VERSION 5.7 ;
  NOWIREEXTENSIONATPIN ON ;
  DIVIDERCHAR "/" ;
  BUSBITCHARS "[]" ;
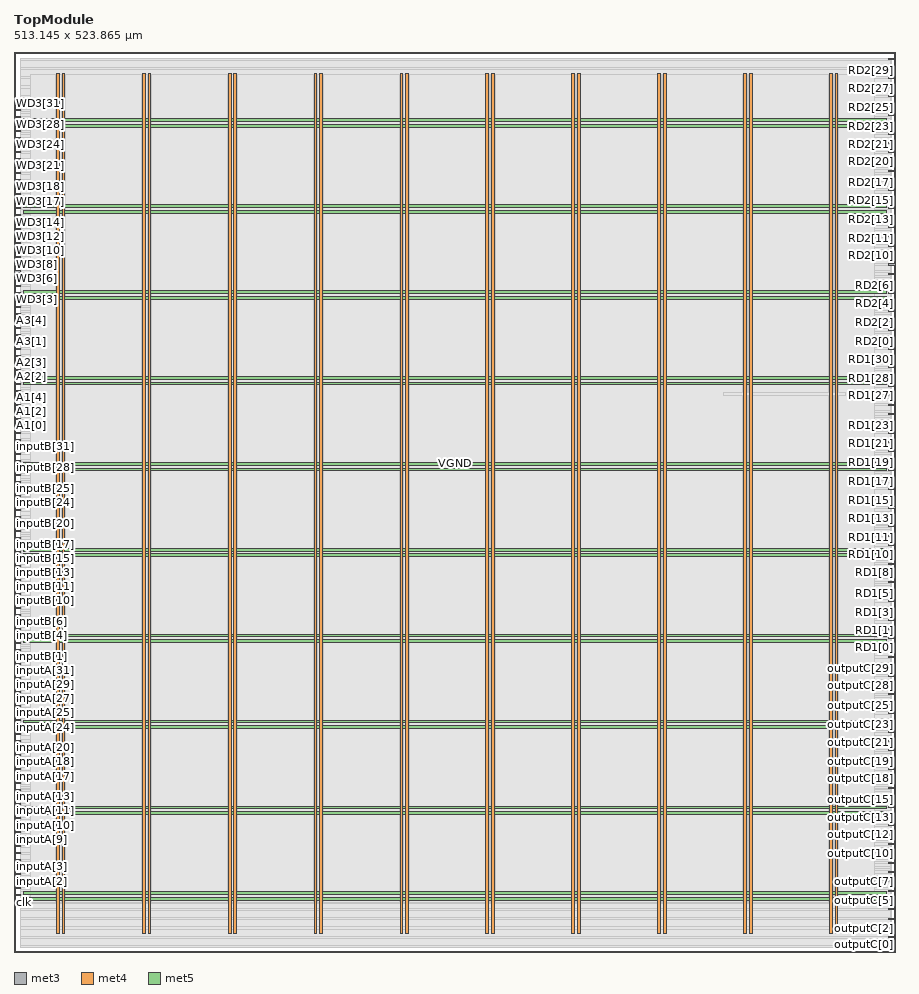
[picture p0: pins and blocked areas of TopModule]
MACRO TopModule
  CLASS BLOCK ;
  FOREIGN TopModule ;
  ORIGIN 0.000 0.000 ;
  SIZE 513.145 BY 523.865 ;
  PIN A1[0]
    DIRECTION INPUT ;
    USE SIGNAL ;
    ANTENNAGATEAREA 2.020500 ;
    ANTENNADIFFAREA 1.738800 ;
    PORT
      LAYER met3 ;
        RECT 0.000 306.040 4.000 306.640 ;
    END
  END A1[0]
  PIN A1[1]
    DIRECTION INPUT ;
    USE SIGNAL ;
    ANTENNAGATEAREA 1.203000 ;
    ANTENNADIFFAREA 1.738800 ;
    PORT
      LAYER met3 ;
        RECT 0.000 310.120 4.000 310.720 ;
    END
  END A1[1]
  PIN A1[2]
    DIRECTION INPUT ;
    USE SIGNAL ;
    ANTENNAGATEAREA 0.426000 ;
    ANTENNADIFFAREA 0.434700 ;
    PORT
      LAYER met3 ;
        RECT 0.000 314.200 4.000 314.800 ;
    END
  END A1[2]
  PIN A1[3]
    DIRECTION INPUT ;
    USE SIGNAL ;
    ANTENNAGATEAREA 1.540500 ;
    ANTENNADIFFAREA 2.608200 ;
    PORT
      LAYER met3 ;
        RECT 0.000 318.280 4.000 318.880 ;
    END
  END A1[3]
  PIN A1[4]
    DIRECTION INPUT ;
    USE SIGNAL ;
    ANTENNAGATEAREA 0.247500 ;
    ANTENNADIFFAREA 0.434700 ;
    PORT
      LAYER met3 ;
        RECT 0.000 322.360 4.000 322.960 ;
    END
  END A1[4]
  PIN A2[0]
    DIRECTION INPUT ;
    USE SIGNAL ;
    ANTENNAGATEAREA 1.629000 ;
    ANTENNADIFFAREA 1.738800 ;
    PORT
      LAYER met3 ;
        RECT 0.000 326.440 4.000 327.040 ;
    END
  END A2[0]
  PIN A2[1]
    DIRECTION INPUT ;
    USE SIGNAL ;
    ANTENNAGATEAREA 1.347000 ;
    ANTENNADIFFAREA 1.738800 ;
    PORT
      LAYER met3 ;
        RECT 0.000 330.520 4.000 331.120 ;
    END
  END A2[1]
  PIN A2[2]
    DIRECTION INPUT ;
    USE SIGNAL ;
    ANTENNAGATEAREA 0.247500 ;
    ANTENNADIFFAREA 0.434700 ;
    PORT
      LAYER met3 ;
        RECT 0.000 334.600 4.000 335.200 ;
    END
  END A2[2]
  PIN A2[3]
    DIRECTION INPUT ;
    USE SIGNAL ;
    ANTENNAGATEAREA 1.327500 ;
    ANTENNADIFFAREA 2.608200 ;
    PORT
      LAYER met3 ;
        RECT 0.000 338.680 4.000 339.280 ;
    END
  END A2[3]
  PIN A2[4]
    DIRECTION INPUT ;
    USE SIGNAL ;
    ANTENNAGATEAREA 0.247500 ;
    ANTENNADIFFAREA 0.434700 ;
    PORT
      LAYER met3 ;
        RECT 0.000 342.760 4.000 343.360 ;
    END
  END A2[4]
  PIN A3[0]
    DIRECTION INPUT ;
    USE SIGNAL ;
    ANTENNAGATEAREA 0.213000 ;
    ANTENNADIFFAREA 0.434700 ;
    PORT
      LAYER met3 ;
        RECT 0.000 346.840 4.000 347.440 ;
    END
  END A3[0]
  PIN A3[1]
    DIRECTION INPUT ;
    USE SIGNAL ;
    ANTENNAGATEAREA 0.247500 ;
    ANTENNADIFFAREA 0.434700 ;
    PORT
      LAYER met3 ;
        RECT 0.000 350.920 4.000 351.520 ;
    END
  END A3[1]
  PIN A3[2]
    DIRECTION INPUT ;
    USE SIGNAL ;
    ANTENNAGATEAREA 0.213000 ;
    ANTENNADIFFAREA 0.434700 ;
    PORT
      LAYER met3 ;
        RECT 0.000 355.000 4.000 355.600 ;
    END
  END A3[2]
  PIN A3[3]
    DIRECTION INPUT ;
    USE SIGNAL ;
    ANTENNAGATEAREA 0.213000 ;
    ANTENNADIFFAREA 0.434700 ;
    PORT
      LAYER met3 ;
        RECT 0.000 359.080 4.000 359.680 ;
    END
  END A3[3]
  PIN A3[4]
    DIRECTION INPUT ;
    USE SIGNAL ;
    ANTENNAGATEAREA 0.213000 ;
    ANTENNADIFFAREA 0.434700 ;
    PORT
      LAYER met3 ;
        RECT 0.000 363.160 4.000 363.760 ;
    END
  END A3[4]
  PIN RD1[0]
    DIRECTION OUTPUT ;
    USE SIGNAL ;
    ANTENNADIFFAREA 0.445500 ;
    PORT
      LAYER met3 ;
        RECT 509.145 176.840 513.145 177.440 ;
    END
  END RD1[0]
  PIN RD1[10]
    DIRECTION OUTPUT ;
    USE SIGNAL ;
    ANTENNADIFFAREA 0.445500 ;
    PORT
      LAYER met3 ;
        RECT 509.145 231.240 513.145 231.840 ;
    END
  END RD1[10]
  PIN RD1[11]
    DIRECTION OUTPUT ;
    USE SIGNAL ;
    ANTENNADIFFAREA 0.445500 ;
    PORT
      LAYER met3 ;
        RECT 509.145 236.680 513.145 237.280 ;
    END
  END RD1[11]
  PIN RD1[12]
    DIRECTION OUTPUT ;
    USE SIGNAL ;
    ANTENNADIFFAREA 0.445500 ;
    PORT
      LAYER met3 ;
        RECT 509.145 242.120 513.145 242.720 ;
    END
  END RD1[12]
  PIN RD1[13]
    DIRECTION OUTPUT ;
    USE SIGNAL ;
    ANTENNADIFFAREA 0.445500 ;
    PORT
      LAYER met3 ;
        RECT 509.145 247.560 513.145 248.160 ;
    END
  END RD1[13]
  PIN RD1[14]
    DIRECTION OUTPUT ;
    USE SIGNAL ;
    ANTENNADIFFAREA 0.445500 ;
    PORT
      LAYER met3 ;
        RECT 509.145 253.000 513.145 253.600 ;
    END
  END RD1[14]
  PIN RD1[15]
    DIRECTION OUTPUT ;
    USE SIGNAL ;
    ANTENNADIFFAREA 0.445500 ;
    PORT
      LAYER met3 ;
        RECT 509.145 258.440 513.145 259.040 ;
    END
  END RD1[15]
  PIN RD1[16]
    DIRECTION OUTPUT ;
    USE SIGNAL ;
    ANTENNADIFFAREA 0.445500 ;
    PORT
      LAYER met3 ;
        RECT 509.145 263.880 513.145 264.480 ;
    END
  END RD1[16]
  PIN RD1[17]
    DIRECTION OUTPUT ;
    USE SIGNAL ;
    ANTENNADIFFAREA 0.445500 ;
    PORT
      LAYER met3 ;
        RECT 509.145 269.320 513.145 269.920 ;
    END
  END RD1[17]
  PIN RD1[18]
    DIRECTION OUTPUT ;
    USE SIGNAL ;
    ANTENNADIFFAREA 0.445500 ;
    PORT
      LAYER met3 ;
        RECT 509.145 274.760 513.145 275.360 ;
    END
  END RD1[18]
  PIN RD1[19]
    DIRECTION OUTPUT ;
    USE SIGNAL ;
    ANTENNADIFFAREA 0.445500 ;
    PORT
      LAYER met3 ;
        RECT 509.145 280.200 513.145 280.800 ;
    END
  END RD1[19]
  PIN RD1[1]
    DIRECTION OUTPUT ;
    USE SIGNAL ;
    ANTENNADIFFAREA 0.445500 ;
    PORT
      LAYER met3 ;
        RECT 509.145 182.280 513.145 182.880 ;
    END
  END RD1[1]
  PIN RD1[20]
    DIRECTION OUTPUT ;
    USE SIGNAL ;
    ANTENNADIFFAREA 0.445500 ;
    PORT
      LAYER met3 ;
        RECT 509.145 285.640 513.145 286.240 ;
    END
  END RD1[20]
  PIN RD1[21]
    DIRECTION OUTPUT ;
    USE SIGNAL ;
    ANTENNADIFFAREA 0.445500 ;
    PORT
      LAYER met3 ;
        RECT 509.145 291.080 513.145 291.680 ;
    END
  END RD1[21]
  PIN RD1[22]
    DIRECTION OUTPUT ;
    USE SIGNAL ;
    ANTENNADIFFAREA 0.445500 ;
    PORT
      LAYER met3 ;
        RECT 509.145 296.520 513.145 297.120 ;
    END
  END RD1[22]
  PIN RD1[23]
    DIRECTION OUTPUT ;
    USE SIGNAL ;
    ANTENNADIFFAREA 0.445500 ;
    PORT
      LAYER met3 ;
        RECT 509.145 301.960 513.145 302.560 ;
    END
  END RD1[23]
  PIN RD1[24]
    DIRECTION OUTPUT ;
    USE SIGNAL ;
    ANTENNADIFFAREA 0.445500 ;
    PORT
      LAYER met3 ;
        RECT 509.145 307.400 513.145 308.000 ;
    END
  END RD1[24]
  PIN RD1[25]
    DIRECTION OUTPUT ;
    USE SIGNAL ;
    ANTENNADIFFAREA 0.445500 ;
    PORT
      LAYER met3 ;
        RECT 509.145 312.840 513.145 313.440 ;
    END
  END RD1[25]
  PIN RD1[26]
    DIRECTION OUTPUT ;
    USE SIGNAL ;
    ANTENNADIFFAREA 0.445500 ;
    PORT
      LAYER met3 ;
        RECT 509.145 318.280 513.145 318.880 ;
    END
  END RD1[26]
  PIN RD1[27]
    DIRECTION OUTPUT ;
    USE SIGNAL ;
    ANTENNADIFFAREA 0.445500 ;
    PORT
      LAYER met3 ;
        RECT 509.145 323.720 513.145 324.320 ;
    END
  END RD1[27]
  PIN RD1[28]
    DIRECTION OUTPUT ;
    USE SIGNAL ;
    ANTENNADIFFAREA 0.445500 ;
    PORT
      LAYER met3 ;
        RECT 509.145 329.160 513.145 329.760 ;
    END
  END RD1[28]
  PIN RD1[29]
    DIRECTION OUTPUT ;
    USE SIGNAL ;
    ANTENNADIFFAREA 0.445500 ;
    PORT
      LAYER met3 ;
        RECT 509.145 334.600 513.145 335.200 ;
    END
  END RD1[29]
  PIN RD1[2]
    DIRECTION OUTPUT ;
    USE SIGNAL ;
    ANTENNADIFFAREA 0.445500 ;
    PORT
      LAYER met3 ;
        RECT 509.145 187.720 513.145 188.320 ;
    END
  END RD1[2]
  PIN RD1[30]
    DIRECTION OUTPUT ;
    USE SIGNAL ;
    ANTENNADIFFAREA 0.445500 ;
    PORT
      LAYER met3 ;
        RECT 509.145 340.040 513.145 340.640 ;
    END
  END RD1[30]
  PIN RD1[31]
    DIRECTION OUTPUT ;
    USE SIGNAL ;
    ANTENNADIFFAREA 0.445500 ;
    PORT
      LAYER met3 ;
        RECT 509.145 345.480 513.145 346.080 ;
    END
  END RD1[31]
  PIN RD1[3]
    DIRECTION OUTPUT ;
    USE SIGNAL ;
    ANTENNADIFFAREA 0.445500 ;
    PORT
      LAYER met3 ;
        RECT 509.145 193.160 513.145 193.760 ;
    END
  END RD1[3]
  PIN RD1[4]
    DIRECTION OUTPUT ;
    USE SIGNAL ;
    ANTENNADIFFAREA 0.445500 ;
    PORT
      LAYER met3 ;
        RECT 509.145 198.600 513.145 199.200 ;
    END
  END RD1[4]
  PIN RD1[5]
    DIRECTION OUTPUT ;
    USE SIGNAL ;
    ANTENNADIFFAREA 0.445500 ;
    PORT
      LAYER met3 ;
        RECT 509.145 204.040 513.145 204.640 ;
    END
  END RD1[5]
  PIN RD1[6]
    DIRECTION OUTPUT ;
    USE SIGNAL ;
    ANTENNADIFFAREA 0.445500 ;
    PORT
      LAYER met3 ;
        RECT 509.145 209.480 513.145 210.080 ;
    END
  END RD1[6]
  PIN RD1[7]
    DIRECTION OUTPUT ;
    USE SIGNAL ;
    ANTENNADIFFAREA 0.445500 ;
    PORT
      LAYER met3 ;
        RECT 509.145 214.920 513.145 215.520 ;
    END
  END RD1[7]
  PIN RD1[8]
    DIRECTION OUTPUT ;
    USE SIGNAL ;
    ANTENNADIFFAREA 0.445500 ;
    PORT
      LAYER met3 ;
        RECT 509.145 220.360 513.145 220.960 ;
    END
  END RD1[8]
  PIN RD1[9]
    DIRECTION OUTPUT ;
    USE SIGNAL ;
    ANTENNADIFFAREA 0.445500 ;
    PORT
      LAYER met3 ;
        RECT 509.145 225.800 513.145 226.400 ;
    END
  END RD1[9]
  PIN RD2[0]
    DIRECTION OUTPUT ;
    USE SIGNAL ;
    ANTENNADIFFAREA 0.445500 ;
    PORT
      LAYER met3 ;
        RECT 509.145 350.920 513.145 351.520 ;
    END
  END RD2[0]
  PIN RD2[10]
    DIRECTION OUTPUT ;
    USE SIGNAL ;
    ANTENNADIFFAREA 0.445500 ;
    PORT
      LAYER met3 ;
        RECT 509.145 405.320 513.145 405.920 ;
    END
  END RD2[10]
  PIN RD2[11]
    DIRECTION OUTPUT ;
    USE SIGNAL ;
    ANTENNADIFFAREA 0.445500 ;
    PORT
      LAYER met3 ;
        RECT 509.145 410.760 513.145 411.360 ;
    END
  END RD2[11]
  PIN RD2[12]
    DIRECTION OUTPUT ;
    USE SIGNAL ;
    ANTENNADIFFAREA 0.445500 ;
    PORT
      LAYER met3 ;
        RECT 509.145 416.200 513.145 416.800 ;
    END
  END RD2[12]
  PIN RD2[13]
    DIRECTION OUTPUT ;
    USE SIGNAL ;
    ANTENNADIFFAREA 0.445500 ;
    PORT
      LAYER met3 ;
        RECT 509.145 421.640 513.145 422.240 ;
    END
  END RD2[13]
  PIN RD2[14]
    DIRECTION OUTPUT ;
    USE SIGNAL ;
    ANTENNADIFFAREA 0.445500 ;
    PORT
      LAYER met3 ;
        RECT 509.145 427.080 513.145 427.680 ;
    END
  END RD2[14]
  PIN RD2[15]
    DIRECTION OUTPUT ;
    USE SIGNAL ;
    ANTENNADIFFAREA 0.445500 ;
    PORT
      LAYER met3 ;
        RECT 509.145 432.520 513.145 433.120 ;
    END
  END RD2[15]
  PIN RD2[16]
    DIRECTION OUTPUT ;
    USE SIGNAL ;
    ANTENNADIFFAREA 0.445500 ;
    PORT
      LAYER met3 ;
        RECT 509.145 437.960 513.145 438.560 ;
    END
  END RD2[16]
  PIN RD2[17]
    DIRECTION OUTPUT ;
    USE SIGNAL ;
    ANTENNADIFFAREA 0.445500 ;
    PORT
      LAYER met3 ;
        RECT 509.145 443.400 513.145 444.000 ;
    END
  END RD2[17]
  PIN RD2[18]
    DIRECTION OUTPUT ;
    USE SIGNAL ;
    ANTENNADIFFAREA 0.445500 ;
    PORT
      LAYER met3 ;
        RECT 509.145 448.840 513.145 449.440 ;
    END
  END RD2[18]
  PIN RD2[19]
    DIRECTION OUTPUT ;
    USE SIGNAL ;
    ANTENNADIFFAREA 0.445500 ;
    PORT
      LAYER met3 ;
        RECT 509.145 454.280 513.145 454.880 ;
    END
  END RD2[19]
  PIN RD2[1]
    DIRECTION OUTPUT ;
    USE SIGNAL ;
    ANTENNADIFFAREA 0.445500 ;
    PORT
      LAYER met3 ;
        RECT 509.145 356.360 513.145 356.960 ;
    END
  END RD2[1]
  PIN RD2[20]
    DIRECTION OUTPUT ;
    USE SIGNAL ;
    ANTENNADIFFAREA 0.445500 ;
    PORT
      LAYER met3 ;
        RECT 509.145 459.720 513.145 460.320 ;
    END
  END RD2[20]
  PIN RD2[21]
    DIRECTION OUTPUT ;
    USE SIGNAL ;
    ANTENNADIFFAREA 0.445500 ;
    PORT
      LAYER met3 ;
        RECT 509.145 465.160 513.145 465.760 ;
    END
  END RD2[21]
  PIN RD2[22]
    DIRECTION OUTPUT ;
    USE SIGNAL ;
    ANTENNADIFFAREA 0.445500 ;
    PORT
      LAYER met3 ;
        RECT 509.145 470.600 513.145 471.200 ;
    END
  END RD2[22]
  PIN RD2[23]
    DIRECTION OUTPUT ;
    USE SIGNAL ;
    ANTENNADIFFAREA 0.445500 ;
    PORT
      LAYER met3 ;
        RECT 509.145 476.040 513.145 476.640 ;
    END
  END RD2[23]
  PIN RD2[24]
    DIRECTION OUTPUT ;
    USE SIGNAL ;
    ANTENNADIFFAREA 0.445500 ;
    PORT
      LAYER met3 ;
        RECT 509.145 481.480 513.145 482.080 ;
    END
  END RD2[24]
  PIN RD2[25]
    DIRECTION OUTPUT ;
    USE SIGNAL ;
    ANTENNADIFFAREA 0.445500 ;
    PORT
      LAYER met3 ;
        RECT 509.145 486.920 513.145 487.520 ;
    END
  END RD2[25]
  PIN RD2[26]
    DIRECTION OUTPUT ;
    USE SIGNAL ;
    ANTENNADIFFAREA 0.445500 ;
    PORT
      LAYER met3 ;
        RECT 509.145 492.360 513.145 492.960 ;
    END
  END RD2[26]
  PIN RD2[27]
    DIRECTION OUTPUT ;
    USE SIGNAL ;
    ANTENNADIFFAREA 0.445500 ;
    PORT
      LAYER met3 ;
        RECT 509.145 497.800 513.145 498.400 ;
    END
  END RD2[27]
  PIN RD2[28]
    DIRECTION OUTPUT ;
    USE SIGNAL ;
    ANTENNADIFFAREA 0.445500 ;
    PORT
      LAYER met3 ;
        RECT 509.145 503.240 513.145 503.840 ;
    END
  END RD2[28]
  PIN RD2[29]
    DIRECTION OUTPUT ;
    USE SIGNAL ;
    ANTENNADIFFAREA 0.445500 ;
    PORT
      LAYER met3 ;
        RECT 509.145 508.680 513.145 509.280 ;
    END
  END RD2[29]
  PIN RD2[2]
    DIRECTION OUTPUT ;
    USE SIGNAL ;
    ANTENNADIFFAREA 0.445500 ;
    PORT
      LAYER met3 ;
        RECT 509.145 361.800 513.145 362.400 ;
    END
  END RD2[2]
  PIN RD2[30]
    DIRECTION OUTPUT ;
    USE SIGNAL ;
    ANTENNADIFFAREA 0.445500 ;
    PORT
      LAYER met3 ;
        RECT 509.145 514.120 513.145 514.720 ;
    END
  END RD2[30]
  PIN RD2[31]
    DIRECTION OUTPUT ;
    USE SIGNAL ;
    ANTENNADIFFAREA 0.795200 ;
    PORT
      LAYER met3 ;
        RECT 509.145 519.560 513.145 520.160 ;
    END
  END RD2[31]
  PIN RD2[3]
    DIRECTION OUTPUT ;
    USE SIGNAL ;
    ANTENNADIFFAREA 0.445500 ;
    PORT
      LAYER met3 ;
        RECT 509.145 367.240 513.145 367.840 ;
    END
  END RD2[3]
  PIN RD2[4]
    DIRECTION OUTPUT ;
    USE SIGNAL ;
    ANTENNADIFFAREA 0.445500 ;
    PORT
      LAYER met3 ;
        RECT 509.145 372.680 513.145 373.280 ;
    END
  END RD2[4]
  PIN RD2[5]
    DIRECTION OUTPUT ;
    USE SIGNAL ;
    ANTENNADIFFAREA 0.445500 ;
    PORT
      LAYER met3 ;
        RECT 509.145 378.120 513.145 378.720 ;
    END
  END RD2[5]
  PIN RD2[6]
    DIRECTION OUTPUT ;
    USE SIGNAL ;
    ANTENNADIFFAREA 0.445500 ;
    PORT
      LAYER met3 ;
        RECT 509.145 383.560 513.145 384.160 ;
    END
  END RD2[6]
  PIN RD2[7]
    DIRECTION OUTPUT ;
    USE SIGNAL ;
    ANTENNADIFFAREA 0.445500 ;
    PORT
      LAYER met3 ;
        RECT 509.145 389.000 513.145 389.600 ;
    END
  END RD2[7]
  PIN RD2[8]
    DIRECTION OUTPUT ;
    USE SIGNAL ;
    ANTENNADIFFAREA 0.445500 ;
    PORT
      LAYER met3 ;
        RECT 509.145 394.440 513.145 395.040 ;
    END
  END RD2[8]
  PIN RD2[9]
    DIRECTION OUTPUT ;
    USE SIGNAL ;
    ANTENNADIFFAREA 0.445500 ;
    PORT
      LAYER met3 ;
        RECT 509.145 399.880 513.145 400.480 ;
    END
  END RD2[9]
  PIN VGND
    DIRECTION INOUT ;
    USE GROUND ;
    PORT
      LAYER met4 ;
        RECT 28.020 10.640 29.620 511.600 ;
    END
    PORT
      LAYER met4 ;
        RECT 78.020 10.640 79.620 511.600 ;
    END
    PORT
      LAYER met4 ;
        RECT 128.020 10.640 129.620 511.600 ;
    END
    PORT
      LAYER met4 ;
        RECT 178.020 10.640 179.620 511.600 ;
    END
    PORT
      LAYER met4 ;
        RECT 228.020 10.640 229.620 511.600 ;
    END
    PORT
      LAYER met4 ;
        RECT 278.020 10.640 279.620 511.600 ;
    END
    PORT
      LAYER met4 ;
        RECT 328.020 10.640 329.620 511.600 ;
    END
    PORT
      LAYER met4 ;
        RECT 378.020 10.640 379.620 511.600 ;
    END
    PORT
      LAYER met4 ;
        RECT 428.020 10.640 429.620 511.600 ;
    END
    PORT
      LAYER met4 ;
        RECT 478.020 10.640 479.620 511.600 ;
    END
    PORT
      LAYER met5 ;
        RECT 5.280 33.380 507.620 34.980 ;
    END
    PORT
      LAYER met5 ;
        RECT 5.280 83.380 507.620 84.980 ;
    END
    PORT
      LAYER met5 ;
        RECT 5.280 133.380 507.620 134.980 ;
    END
    PORT
      LAYER met5 ;
        RECT 5.280 183.380 507.620 184.980 ;
    END
    PORT
      LAYER met5 ;
        RECT 5.280 233.380 507.620 234.980 ;
    END
    PORT
      LAYER met5 ;
        RECT 5.280 283.380 507.620 284.980 ;
    END
    PORT
      LAYER met5 ;
        RECT 5.280 333.380 507.620 334.980 ;
    END
    PORT
      LAYER met5 ;
        RECT 5.280 383.380 507.620 384.980 ;
    END
    PORT
      LAYER met5 ;
        RECT 5.280 433.380 507.620 434.980 ;
    END
    PORT
      LAYER met5 ;
        RECT 5.280 483.380 507.620 484.980 ;
    END
  END VGND
  PIN VPWR
    DIRECTION INOUT ;
    USE POWER ;
    PORT
      LAYER met4 ;
        RECT 24.720 10.640 26.320 511.600 ;
    END
    PORT
      LAYER met4 ;
        RECT 74.720 10.640 76.320 511.600 ;
    END
    PORT
      LAYER met4 ;
        RECT 124.720 10.640 126.320 511.600 ;
    END
    PORT
      LAYER met4 ;
        RECT 174.720 10.640 176.320 511.600 ;
    END
    PORT
      LAYER met4 ;
        RECT 224.720 10.640 226.320 511.600 ;
    END
    PORT
      LAYER met4 ;
        RECT 274.720 10.640 276.320 511.600 ;
    END
    PORT
      LAYER met4 ;
        RECT 324.720 10.640 326.320 511.600 ;
    END
    PORT
      LAYER met4 ;
        RECT 374.720 10.640 376.320 511.600 ;
    END
    PORT
      LAYER met4 ;
        RECT 424.720 10.640 426.320 511.600 ;
    END
    PORT
      LAYER met4 ;
        RECT 474.720 10.640 476.320 511.600 ;
    END
    PORT
      LAYER met5 ;
        RECT 5.280 30.080 507.620 31.680 ;
    END
    PORT
      LAYER met5 ;
        RECT 5.280 80.080 507.620 81.680 ;
    END
    PORT
      LAYER met5 ;
        RECT 5.280 130.080 507.620 131.680 ;
    END
    PORT
      LAYER met5 ;
        RECT 5.280 180.080 507.620 181.680 ;
    END
    PORT
      LAYER met5 ;
        RECT 5.280 230.080 507.620 231.680 ;
    END
    PORT
      LAYER met5 ;
        RECT 5.280 280.080 507.620 281.680 ;
    END
    PORT
      LAYER met5 ;
        RECT 5.280 330.080 507.620 331.680 ;
    END
    PORT
      LAYER met5 ;
        RECT 5.280 380.080 507.620 381.680 ;
    END
    PORT
      LAYER met5 ;
        RECT 5.280 430.080 507.620 431.680 ;
    END
    PORT
      LAYER met5 ;
        RECT 5.280 480.080 507.620 481.680 ;
    END
  END VPWR
  PIN WD3[0]
    DIRECTION INPUT ;
    USE SIGNAL ;
    ANTENNAGATEAREA 0.213000 ;
    ANTENNADIFFAREA 0.434700 ;
    PORT
      LAYER met3 ;
        RECT 0.000 367.240 4.000 367.840 ;
    END
  END WD3[0]
  PIN WD3[10]
    DIRECTION INPUT ;
    USE SIGNAL ;
    ANTENNAGATEAREA 0.213000 ;
    ANTENNADIFFAREA 0.434700 ;
    PORT
      LAYER met3 ;
        RECT 0.000 408.040 4.000 408.640 ;
    END
  END WD3[10]
  PIN WD3[11]
    DIRECTION INPUT ;
    USE SIGNAL ;
    ANTENNAGATEAREA 0.213000 ;
    ANTENNADIFFAREA 0.434700 ;
    PORT
      LAYER met3 ;
        RECT 0.000 412.120 4.000 412.720 ;
    END
  END WD3[11]
  PIN WD3[12]
    DIRECTION INPUT ;
    USE SIGNAL ;
    ANTENNAGATEAREA 0.213000 ;
    ANTENNADIFFAREA 0.434700 ;
    PORT
      LAYER met3 ;
        RECT 0.000 416.200 4.000 416.800 ;
    END
  END WD3[12]
  PIN WD3[13]
    DIRECTION INPUT ;
    USE SIGNAL ;
    ANTENNAGATEAREA 0.213000 ;
    ANTENNADIFFAREA 0.434700 ;
    PORT
      LAYER met3 ;
        RECT 0.000 420.280 4.000 420.880 ;
    END
  END WD3[13]
  PIN WD3[14]
    DIRECTION INPUT ;
    USE SIGNAL ;
    ANTENNAGATEAREA 0.213000 ;
    ANTENNADIFFAREA 0.434700 ;
    PORT
      LAYER met3 ;
        RECT 0.000 424.360 4.000 424.960 ;
    END
  END WD3[14]
  PIN WD3[15]
    DIRECTION INPUT ;
    USE SIGNAL ;
    ANTENNAGATEAREA 0.213000 ;
    ANTENNADIFFAREA 0.434700 ;
    PORT
      LAYER met3 ;
        RECT 0.000 428.440 4.000 429.040 ;
    END
  END WD3[15]
  PIN WD3[16]
    DIRECTION INPUT ;
    USE SIGNAL ;
    ANTENNAGATEAREA 0.213000 ;
    ANTENNADIFFAREA 0.434700 ;
    PORT
      LAYER met3 ;
        RECT 0.000 432.520 4.000 433.120 ;
    END
  END WD3[16]
  PIN WD3[17]
    DIRECTION INPUT ;
    USE SIGNAL ;
    ANTENNAGATEAREA 0.213000 ;
    ANTENNADIFFAREA 0.434700 ;
    PORT
      LAYER met3 ;
        RECT 0.000 436.600 4.000 437.200 ;
    END
  END WD3[17]
  PIN WD3[18]
    DIRECTION INPUT ;
    USE SIGNAL ;
    ANTENNAGATEAREA 0.213000 ;
    ANTENNADIFFAREA 0.434700 ;
    PORT
      LAYER met3 ;
        RECT 0.000 440.680 4.000 441.280 ;
    END
  END WD3[18]
  PIN WD3[19]
    DIRECTION INPUT ;
    USE SIGNAL ;
    ANTENNAGATEAREA 0.213000 ;
    ANTENNADIFFAREA 0.434700 ;
    PORT
      LAYER met3 ;
        RECT 0.000 444.760 4.000 445.360 ;
    END
  END WD3[19]
  PIN WD3[1]
    DIRECTION INPUT ;
    USE SIGNAL ;
    ANTENNAGATEAREA 0.213000 ;
    ANTENNADIFFAREA 0.434700 ;
    PORT
      LAYER met3 ;
        RECT 0.000 371.320 4.000 371.920 ;
    END
  END WD3[1]
  PIN WD3[20]
    DIRECTION INPUT ;
    USE SIGNAL ;
    ANTENNAGATEAREA 0.213000 ;
    ANTENNADIFFAREA 0.434700 ;
    PORT
      LAYER met3 ;
        RECT 0.000 448.840 4.000 449.440 ;
    END
  END WD3[20]
  PIN WD3[21]
    DIRECTION INPUT ;
    USE SIGNAL ;
    ANTENNAGATEAREA 0.213000 ;
    ANTENNADIFFAREA 0.434700 ;
    PORT
      LAYER met3 ;
        RECT 0.000 452.920 4.000 453.520 ;
    END
  END WD3[21]
  PIN WD3[22]
    DIRECTION INPUT ;
    USE SIGNAL ;
    ANTENNAGATEAREA 0.159000 ;
    ANTENNADIFFAREA 0.434700 ;
    PORT
      LAYER met3 ;
        RECT 0.000 457.000 4.000 457.600 ;
    END
  END WD3[22]
  PIN WD3[23]
    DIRECTION INPUT ;
    USE SIGNAL ;
    ANTENNAGATEAREA 0.213000 ;
    ANTENNADIFFAREA 0.434700 ;
    PORT
      LAYER met3 ;
        RECT 0.000 461.080 4.000 461.680 ;
    END
  END WD3[23]
  PIN WD3[24]
    DIRECTION INPUT ;
    USE SIGNAL ;
    ANTENNAGATEAREA 0.213000 ;
    ANTENNADIFFAREA 0.434700 ;
    PORT
      LAYER met3 ;
        RECT 0.000 465.160 4.000 465.760 ;
    END
  END WD3[24]
  PIN WD3[25]
    DIRECTION INPUT ;
    USE SIGNAL ;
    ANTENNAGATEAREA 0.213000 ;
    ANTENNADIFFAREA 0.434700 ;
    PORT
      LAYER met3 ;
        RECT 0.000 469.240 4.000 469.840 ;
    END
  END WD3[25]
  PIN WD3[26]
    DIRECTION INPUT ;
    USE SIGNAL ;
    ANTENNAGATEAREA 0.213000 ;
    ANTENNADIFFAREA 0.434700 ;
    PORT
      LAYER met3 ;
        RECT 0.000 473.320 4.000 473.920 ;
    END
  END WD3[26]
  PIN WD3[27]
    DIRECTION INPUT ;
    USE SIGNAL ;
    ANTENNAGATEAREA 0.213000 ;
    ANTENNADIFFAREA 0.434700 ;
    PORT
      LAYER met3 ;
        RECT 0.000 477.400 4.000 478.000 ;
    END
  END WD3[27]
  PIN WD3[28]
    DIRECTION INPUT ;
    USE SIGNAL ;
    ANTENNAGATEAREA 0.213000 ;
    ANTENNADIFFAREA 0.434700 ;
    PORT
      LAYER met3 ;
        RECT 0.000 481.480 4.000 482.080 ;
    END
  END WD3[28]
  PIN WD3[29]
    DIRECTION INPUT ;
    USE SIGNAL ;
    ANTENNAGATEAREA 0.213000 ;
    ANTENNADIFFAREA 0.434700 ;
    PORT
      LAYER met3 ;
        RECT 0.000 485.560 4.000 486.160 ;
    END
  END WD3[29]
  PIN WD3[2]
    DIRECTION INPUT ;
    USE SIGNAL ;
    ANTENNAGATEAREA 0.213000 ;
    ANTENNADIFFAREA 0.434700 ;
    PORT
      LAYER met3 ;
        RECT 0.000 375.400 4.000 376.000 ;
    END
  END WD3[2]
  PIN WD3[30]
    DIRECTION INPUT ;
    USE SIGNAL ;
    ANTENNAGATEAREA 0.247500 ;
    ANTENNADIFFAREA 0.434700 ;
    PORT
      LAYER met3 ;
        RECT 0.000 489.640 4.000 490.240 ;
    END
  END WD3[30]
  PIN WD3[31]
    DIRECTION INPUT ;
    USE SIGNAL ;
    ANTENNAGATEAREA 0.247500 ;
    ANTENNADIFFAREA 0.434700 ;
    PORT
      LAYER met3 ;
        RECT 0.000 493.720 4.000 494.320 ;
    END
  END WD3[31]
  PIN WD3[3]
    DIRECTION INPUT ;
    USE SIGNAL ;
    ANTENNAGATEAREA 0.247500 ;
    ANTENNADIFFAREA 0.434700 ;
    PORT
      LAYER met3 ;
        RECT 0.000 379.480 4.000 380.080 ;
    END
  END WD3[3]
  PIN WD3[4]
    DIRECTION INPUT ;
    USE SIGNAL ;
    ANTENNAGATEAREA 0.213000 ;
    ANTENNADIFFAREA 0.434700 ;
    PORT
      LAYER met3 ;
        RECT 0.000 383.560 4.000 384.160 ;
    END
  END WD3[4]
  PIN WD3[5]
    DIRECTION INPUT ;
    USE SIGNAL ;
    ANTENNAGATEAREA 0.213000 ;
    ANTENNADIFFAREA 0.434700 ;
    PORT
      LAYER met3 ;
        RECT 0.000 387.640 4.000 388.240 ;
    END
  END WD3[5]
  PIN WD3[6]
    DIRECTION INPUT ;
    USE SIGNAL ;
    ANTENNAGATEAREA 0.247500 ;
    ANTENNADIFFAREA 0.434700 ;
    PORT
      LAYER met3 ;
        RECT 0.000 391.720 4.000 392.320 ;
    END
  END WD3[6]
  PIN WD3[7]
    DIRECTION INPUT ;
    USE SIGNAL ;
    ANTENNAGATEAREA 0.247500 ;
    ANTENNADIFFAREA 0.434700 ;
    PORT
      LAYER met3 ;
        RECT 0.000 395.800 4.000 396.400 ;
    END
  END WD3[7]
  PIN WD3[8]
    DIRECTION INPUT ;
    USE SIGNAL ;
    ANTENNAGATEAREA 0.213000 ;
    ANTENNADIFFAREA 0.434700 ;
    PORT
      LAYER met3 ;
        RECT 0.000 399.880 4.000 400.480 ;
    END
  END WD3[8]
  PIN WD3[9]
    DIRECTION INPUT ;
    USE SIGNAL ;
    ANTENNAGATEAREA 0.247500 ;
    ANTENNADIFFAREA 0.434700 ;
    PORT
      LAYER met3 ;
        RECT 0.000 403.960 4.000 404.560 ;
    END
  END WD3[9]
  PIN WE3
    DIRECTION INPUT ;
    USE SIGNAL ;
    ANTENNAGATEAREA 0.247500 ;
    ANTENNADIFFAREA 0.434700 ;
    PORT
      LAYER met3 ;
        RECT 0.000 301.960 4.000 302.560 ;
    END
  END WE3
  PIN clk
    DIRECTION INPUT ;
    USE SIGNAL ;
    ANTENNAGATEAREA 0.852000 ;
    ANTENNADIFFAREA 0.434700 ;
    PORT
      LAYER met3 ;
        RECT 0.000 28.600 4.000 29.200 ;
    END
  END clk
  PIN inputA[0]
    DIRECTION INPUT ;
    USE SIGNAL ;
    ANTENNAGATEAREA 0.196500 ;
    ANTENNADIFFAREA 0.434700 ;
    PORT
      LAYER met3 ;
        RECT 0.000 32.680 4.000 33.280 ;
    END
  END inputA[0]
  PIN inputA[10]
    DIRECTION INPUT ;
    USE SIGNAL ;
    ANTENNAGATEAREA 0.196500 ;
    ANTENNADIFFAREA 0.434700 ;
    PORT
      LAYER met3 ;
        RECT 0.000 73.480 4.000 74.080 ;
    END
  END inputA[10]
  PIN inputA[11]
    DIRECTION INPUT ;
    USE SIGNAL ;
    ANTENNAGATEAREA 0.196500 ;
    ANTENNADIFFAREA 0.434700 ;
    PORT
      LAYER met3 ;
        RECT 0.000 77.560 4.000 78.160 ;
    END
  END inputA[11]
  PIN inputA[12]
    DIRECTION INPUT ;
    USE SIGNAL ;
    ANTENNAGATEAREA 0.126000 ;
    ANTENNADIFFAREA 0.434700 ;
    PORT
      LAYER met3 ;
        RECT 0.000 81.640 4.000 82.240 ;
    END
  END inputA[12]
  PIN inputA[13]
    DIRECTION INPUT ;
    USE SIGNAL ;
    ANTENNAGATEAREA 0.126000 ;
    ANTENNADIFFAREA 0.434700 ;
    PORT
      LAYER met3 ;
        RECT 0.000 85.720 4.000 86.320 ;
    END
  END inputA[13]
  PIN inputA[14]
    DIRECTION INPUT ;
    USE SIGNAL ;
    ANTENNAGATEAREA 0.196500 ;
    ANTENNADIFFAREA 0.434700 ;
    PORT
      LAYER met3 ;
        RECT 0.000 89.800 4.000 90.400 ;
    END
  END inputA[14]
  PIN inputA[15]
    DIRECTION INPUT ;
    USE SIGNAL ;
    ANTENNAGATEAREA 0.196500 ;
    ANTENNADIFFAREA 0.434700 ;
    PORT
      LAYER met3 ;
        RECT 0.000 93.880 4.000 94.480 ;
    END
  END inputA[15]
  PIN inputA[16]
    DIRECTION INPUT ;
    USE SIGNAL ;
    ANTENNAGATEAREA 0.196500 ;
    ANTENNADIFFAREA 0.434700 ;
    PORT
      LAYER met3 ;
        RECT 0.000 97.960 4.000 98.560 ;
    END
  END inputA[16]
  PIN inputA[17]
    DIRECTION INPUT ;
    USE SIGNAL ;
    ANTENNAGATEAREA 0.196500 ;
    ANTENNADIFFAREA 0.434700 ;
    PORT
      LAYER met3 ;
        RECT 0.000 102.040 4.000 102.640 ;
    END
  END inputA[17]
  PIN inputA[18]
    DIRECTION INPUT ;
    USE SIGNAL ;
    ANTENNAGATEAREA 0.196500 ;
    ANTENNADIFFAREA 0.434700 ;
    PORT
      LAYER met3 ;
        RECT 0.000 106.120 4.000 106.720 ;
    END
  END inputA[18]
  PIN inputA[19]
    DIRECTION INPUT ;
    USE SIGNAL ;
    ANTENNAGATEAREA 0.213000 ;
    ANTENNADIFFAREA 0.434700 ;
    PORT
      LAYER met3 ;
        RECT 0.000 110.200 4.000 110.800 ;
    END
  END inputA[19]
  PIN inputA[1]
    DIRECTION INPUT ;
    USE SIGNAL ;
    ANTENNAGATEAREA 0.196500 ;
    ANTENNADIFFAREA 0.434700 ;
    PORT
      LAYER met3 ;
        RECT 0.000 36.760 4.000 37.360 ;
    END
  END inputA[1]
  PIN inputA[20]
    DIRECTION INPUT ;
    USE SIGNAL ;
    ANTENNAGATEAREA 0.126000 ;
    ANTENNADIFFAREA 0.434700 ;
    PORT
      LAYER met3 ;
        RECT 0.000 114.280 4.000 114.880 ;
    END
  END inputA[20]
  PIN inputA[21]
    DIRECTION INPUT ;
    USE SIGNAL ;
    ANTENNAGATEAREA 0.213000 ;
    ANTENNADIFFAREA 0.434700 ;
    PORT
      LAYER met3 ;
        RECT 0.000 118.360 4.000 118.960 ;
    END
  END inputA[21]
  PIN inputA[22]
    DIRECTION INPUT ;
    USE SIGNAL ;
    ANTENNAGATEAREA 0.196500 ;
    ANTENNADIFFAREA 0.434700 ;
    PORT
      LAYER met3 ;
        RECT 0.000 122.440 4.000 123.040 ;
    END
  END inputA[22]
  PIN inputA[23]
    DIRECTION INPUT ;
    USE SIGNAL ;
    ANTENNAGATEAREA 0.196500 ;
    ANTENNADIFFAREA 0.434700 ;
    PORT
      LAYER met3 ;
        RECT 0.000 126.520 4.000 127.120 ;
    END
  END inputA[23]
  PIN inputA[24]
    DIRECTION INPUT ;
    USE SIGNAL ;
    ANTENNAGATEAREA 0.196500 ;
    ANTENNADIFFAREA 0.434700 ;
    PORT
      LAYER met3 ;
        RECT 0.000 130.600 4.000 131.200 ;
    END
  END inputA[24]
  PIN inputA[25]
    DIRECTION INPUT ;
    USE SIGNAL ;
    ANTENNAGATEAREA 0.196500 ;
    ANTENNADIFFAREA 0.434700 ;
    PORT
      LAYER met3 ;
        RECT 0.000 134.680 4.000 135.280 ;
    END
  END inputA[25]
  PIN inputA[26]
    DIRECTION INPUT ;
    USE SIGNAL ;
    ANTENNAGATEAREA 0.213000 ;
    ANTENNADIFFAREA 0.434700 ;
    PORT
      LAYER met3 ;
        RECT 0.000 138.760 4.000 139.360 ;
    END
  END inputA[26]
  PIN inputA[27]
    DIRECTION INPUT ;
    USE SIGNAL ;
    ANTENNAGATEAREA 0.213000 ;
    ANTENNADIFFAREA 0.434700 ;
    PORT
      LAYER met3 ;
        RECT 0.000 142.840 4.000 143.440 ;
    END
  END inputA[27]
  PIN inputA[28]
    DIRECTION INPUT ;
    USE SIGNAL ;
    ANTENNAGATEAREA 0.196500 ;
    ANTENNADIFFAREA 0.434700 ;
    PORT
      LAYER met3 ;
        RECT 0.000 146.920 4.000 147.520 ;
    END
  END inputA[28]
  PIN inputA[29]
    DIRECTION INPUT ;
    USE SIGNAL ;
    ANTENNAGATEAREA 0.126000 ;
    ANTENNADIFFAREA 0.434700 ;
    PORT
      LAYER met3 ;
        RECT 0.000 151.000 4.000 151.600 ;
    END
  END inputA[29]
  PIN inputA[2]
    DIRECTION INPUT ;
    USE SIGNAL ;
    ANTENNAGATEAREA 0.196500 ;
    ANTENNADIFFAREA 0.434700 ;
    PORT
      LAYER met3 ;
        RECT 0.000 40.840 4.000 41.440 ;
    END
  END inputA[2]
  PIN inputA[30]
    DIRECTION INPUT ;
    USE SIGNAL ;
    ANTENNAGATEAREA 0.213000 ;
    ANTENNADIFFAREA 0.434700 ;
    PORT
      LAYER met3 ;
        RECT 0.000 155.080 4.000 155.680 ;
    END
  END inputA[30]
  PIN inputA[31]
    DIRECTION INPUT ;
    USE SIGNAL ;
    ANTENNAGATEAREA 0.196500 ;
    ANTENNADIFFAREA 0.434700 ;
    PORT
      LAYER met3 ;
        RECT 0.000 159.160 4.000 159.760 ;
    END
  END inputA[31]
  PIN inputA[3]
    DIRECTION INPUT ;
    USE SIGNAL ;
    ANTENNAGATEAREA 0.196500 ;
    ANTENNADIFFAREA 0.434700 ;
    PORT
      LAYER met3 ;
        RECT 0.000 44.920 4.000 45.520 ;
    END
  END inputA[3]
  PIN inputA[4]
    DIRECTION INPUT ;
    USE SIGNAL ;
    ANTENNAGATEAREA 0.126000 ;
    ANTENNADIFFAREA 0.434700 ;
    PORT
      LAYER met3 ;
        RECT 0.000 49.000 4.000 49.600 ;
    END
  END inputA[4]
  PIN inputA[5]
    DIRECTION INPUT ;
    USE SIGNAL ;
    ANTENNAGATEAREA 0.126000 ;
    ANTENNADIFFAREA 0.434700 ;
    PORT
      LAYER met3 ;
        RECT 0.000 53.080 4.000 53.680 ;
    END
  END inputA[5]
  PIN inputA[6]
    DIRECTION INPUT ;
    USE SIGNAL ;
    ANTENNAGATEAREA 0.196500 ;
    ANTENNADIFFAREA 0.434700 ;
    PORT
      LAYER met3 ;
        RECT 0.000 57.160 4.000 57.760 ;
    END
  END inputA[6]
  PIN inputA[7]
    DIRECTION INPUT ;
    USE SIGNAL ;
    ANTENNAGATEAREA 0.196500 ;
    ANTENNADIFFAREA 0.434700 ;
    PORT
      LAYER met3 ;
        RECT 0.000 61.240 4.000 61.840 ;
    END
  END inputA[7]
  PIN inputA[8]
    DIRECTION INPUT ;
    USE SIGNAL ;
    ANTENNAGATEAREA 0.196500 ;
    ANTENNADIFFAREA 0.434700 ;
    PORT
      LAYER met3 ;
        RECT 0.000 65.320 4.000 65.920 ;
    END
  END inputA[8]
  PIN inputA[9]
    DIRECTION INPUT ;
    USE SIGNAL ;
    ANTENNAGATEAREA 0.196500 ;
    ANTENNADIFFAREA 0.434700 ;
    PORT
      LAYER met3 ;
        RECT 0.000 69.400 4.000 70.000 ;
    END
  END inputA[9]
  PIN inputB[0]
    DIRECTION INPUT ;
    USE SIGNAL ;
    ANTENNAGATEAREA 0.196500 ;
    ANTENNADIFFAREA 0.434700 ;
    PORT
      LAYER met3 ;
        RECT 0.000 163.240 4.000 163.840 ;
    END
  END inputB[0]
  PIN inputB[10]
    DIRECTION INPUT ;
    USE SIGNAL ;
    ANTENNAGATEAREA 0.196500 ;
    ANTENNADIFFAREA 0.434700 ;
    PORT
      LAYER met3 ;
        RECT 0.000 204.040 4.000 204.640 ;
    END
  END inputB[10]
  PIN inputB[11]
    DIRECTION INPUT ;
    USE SIGNAL ;
    ANTENNAGATEAREA 0.196500 ;
    ANTENNADIFFAREA 0.434700 ;
    PORT
      LAYER met3 ;
        RECT 0.000 208.120 4.000 208.720 ;
    END
  END inputB[11]
  PIN inputB[12]
    DIRECTION INPUT ;
    USE SIGNAL ;
    ANTENNAGATEAREA 0.213000 ;
    ANTENNADIFFAREA 0.434700 ;
    PORT
      LAYER met3 ;
        RECT 0.000 212.200 4.000 212.800 ;
    END
  END inputB[12]
  PIN inputB[13]
    DIRECTION INPUT ;
    USE SIGNAL ;
    ANTENNAGATEAREA 0.126000 ;
    ANTENNADIFFAREA 0.434700 ;
    PORT
      LAYER met3 ;
        RECT 0.000 216.280 4.000 216.880 ;
    END
  END inputB[13]
  PIN inputB[14]
    DIRECTION INPUT ;
    USE SIGNAL ;
    ANTENNAGATEAREA 0.196500 ;
    ANTENNADIFFAREA 0.434700 ;
    PORT
      LAYER met3 ;
        RECT 0.000 220.360 4.000 220.960 ;
    END
  END inputB[14]
  PIN inputB[15]
    DIRECTION INPUT ;
    USE SIGNAL ;
    ANTENNAGATEAREA 0.196500 ;
    ANTENNADIFFAREA 0.434700 ;
    PORT
      LAYER met3 ;
        RECT 0.000 224.440 4.000 225.040 ;
    END
  END inputB[15]
  PIN inputB[16]
    DIRECTION INPUT ;
    USE SIGNAL ;
    ANTENNAGATEAREA 0.196500 ;
    ANTENNADIFFAREA 0.434700 ;
    PORT
      LAYER met3 ;
        RECT 0.000 228.520 4.000 229.120 ;
    END
  END inputB[16]
  PIN inputB[17]
    DIRECTION INPUT ;
    USE SIGNAL ;
    ANTENNAGATEAREA 0.196500 ;
    ANTENNADIFFAREA 0.434700 ;
    PORT
      LAYER met3 ;
        RECT 0.000 232.600 4.000 233.200 ;
    END
  END inputB[17]
  PIN inputB[18]
    DIRECTION INPUT ;
    USE SIGNAL ;
    ANTENNAGATEAREA 0.196500 ;
    ANTENNADIFFAREA 0.434700 ;
    PORT
      LAYER met3 ;
        RECT 0.000 236.680 4.000 237.280 ;
    END
  END inputB[18]
  PIN inputB[19]
    DIRECTION INPUT ;
    USE SIGNAL ;
    ANTENNAGATEAREA 0.196500 ;
    ANTENNADIFFAREA 0.434700 ;
    PORT
      LAYER met3 ;
        RECT 0.000 240.760 4.000 241.360 ;
    END
  END inputB[19]
  PIN inputB[1]
    DIRECTION INPUT ;
    USE SIGNAL ;
    ANTENNAGATEAREA 0.495000 ;
    ANTENNADIFFAREA 0.434700 ;
    PORT
      LAYER met3 ;
        RECT 0.000 167.320 4.000 167.920 ;
    END
  END inputB[1]
  PIN inputB[20]
    DIRECTION INPUT ;
    USE SIGNAL ;
    ANTENNAGATEAREA 0.196500 ;
    ANTENNADIFFAREA 0.434700 ;
    PORT
      LAYER met3 ;
        RECT 0.000 244.840 4.000 245.440 ;
    END
  END inputB[20]
  PIN inputB[21]
    DIRECTION INPUT ;
    USE SIGNAL ;
    ANTENNAGATEAREA 0.126000 ;
    ANTENNADIFFAREA 0.434700 ;
    PORT
      LAYER met3 ;
        RECT 0.000 248.920 4.000 249.520 ;
    END
  END inputB[21]
  PIN inputB[22]
    DIRECTION INPUT ;
    USE SIGNAL ;
    ANTENNAGATEAREA 0.196500 ;
    ANTENNADIFFAREA 0.434700 ;
    PORT
      LAYER met3 ;
        RECT 0.000 253.000 4.000 253.600 ;
    END
  END inputB[22]
  PIN inputB[23]
    DIRECTION INPUT ;
    USE SIGNAL ;
    ANTENNAGATEAREA 0.196500 ;
    ANTENNADIFFAREA 0.434700 ;
    PORT
      LAYER met3 ;
        RECT 0.000 257.080 4.000 257.680 ;
    END
  END inputB[23]
  PIN inputB[24]
    DIRECTION INPUT ;
    USE SIGNAL ;
    ANTENNAGATEAREA 0.213000 ;
    ANTENNADIFFAREA 0.434700 ;
    PORT
      LAYER met3 ;
        RECT 0.000 261.160 4.000 261.760 ;
    END
  END inputB[24]
  PIN inputB[25]
    DIRECTION INPUT ;
    USE SIGNAL ;
    ANTENNAGATEAREA 0.126000 ;
    ANTENNADIFFAREA 0.434700 ;
    PORT
      LAYER met3 ;
        RECT 0.000 265.240 4.000 265.840 ;
    END
  END inputB[25]
  PIN inputB[26]
    DIRECTION INPUT ;
    USE SIGNAL ;
    ANTENNAGATEAREA 0.213000 ;
    ANTENNADIFFAREA 0.434700 ;
    PORT
      LAYER met3 ;
        RECT 0.000 269.320 4.000 269.920 ;
    END
  END inputB[26]
  PIN inputB[27]
    DIRECTION INPUT ;
    USE SIGNAL ;
    ANTENNAGATEAREA 0.213000 ;
    ANTENNADIFFAREA 0.434700 ;
    PORT
      LAYER met3 ;
        RECT 0.000 273.400 4.000 274.000 ;
    END
  END inputB[27]
  PIN inputB[28]
    DIRECTION INPUT ;
    USE SIGNAL ;
    ANTENNAGATEAREA 0.213000 ;
    ANTENNADIFFAREA 0.434700 ;
    PORT
      LAYER met3 ;
        RECT 0.000 277.480 4.000 278.080 ;
    END
  END inputB[28]
  PIN inputB[29]
    DIRECTION INPUT ;
    USE SIGNAL ;
    ANTENNAGATEAREA 0.213000 ;
    ANTENNADIFFAREA 0.434700 ;
    PORT
      LAYER met3 ;
        RECT 0.000 281.560 4.000 282.160 ;
    END
  END inputB[29]
  PIN inputB[2]
    DIRECTION INPUT ;
    USE SIGNAL ;
    ANTENNAGATEAREA 0.247500 ;
    ANTENNADIFFAREA 0.434700 ;
    PORT
      LAYER met3 ;
        RECT 0.000 171.400 4.000 172.000 ;
    END
  END inputB[2]
  PIN inputB[30]
    DIRECTION INPUT ;
    USE SIGNAL ;
    ANTENNAGATEAREA 0.213000 ;
    ANTENNADIFFAREA 0.434700 ;
    PORT
      LAYER met3 ;
        RECT 0.000 285.640 4.000 286.240 ;
    END
  END inputB[30]
  PIN inputB[31]
    DIRECTION INPUT ;
    USE SIGNAL ;
    ANTENNAGATEAREA 0.126000 ;
    ANTENNADIFFAREA 0.434700 ;
    PORT
      LAYER met3 ;
        RECT 0.000 289.720 4.000 290.320 ;
    END
  END inputB[31]
  PIN inputB[3]
    DIRECTION INPUT ;
    USE SIGNAL ;
    ANTENNAGATEAREA 0.126000 ;
    ANTENNADIFFAREA 0.434700 ;
    PORT
      LAYER met3 ;
        RECT 0.000 175.480 4.000 176.080 ;
    END
  END inputB[3]
  PIN inputB[4]
    DIRECTION INPUT ;
    USE SIGNAL ;
    ANTENNAGATEAREA 0.196500 ;
    ANTENNADIFFAREA 0.434700 ;
    PORT
      LAYER met3 ;
        RECT 0.000 179.560 4.000 180.160 ;
    END
  END inputB[4]
  PIN inputB[5]
    DIRECTION INPUT ;
    USE SIGNAL ;
    ANTENNAGATEAREA 0.196500 ;
    ANTENNADIFFAREA 0.434700 ;
    PORT
      LAYER met3 ;
        RECT 0.000 183.640 4.000 184.240 ;
    END
  END inputB[5]
  PIN inputB[6]
    DIRECTION INPUT ;
    USE SIGNAL ;
    ANTENNAGATEAREA 0.126000 ;
    ANTENNADIFFAREA 0.434700 ;
    PORT
      LAYER met3 ;
        RECT 0.000 187.720 4.000 188.320 ;
    END
  END inputB[6]
  PIN inputB[7]
    DIRECTION INPUT ;
    USE SIGNAL ;
    ANTENNAGATEAREA 0.196500 ;
    ANTENNADIFFAREA 0.434700 ;
    PORT
      LAYER met3 ;
        RECT 0.000 191.800 4.000 192.400 ;
    END
  END inputB[7]
  PIN inputB[8]
    DIRECTION INPUT ;
    USE SIGNAL ;
    ANTENNAGATEAREA 0.196500 ;
    ANTENNADIFFAREA 0.434700 ;
    PORT
      LAYER met3 ;
        RECT 0.000 195.880 4.000 196.480 ;
    END
  END inputB[8]
  PIN inputB[9]
    DIRECTION INPUT ;
    USE SIGNAL ;
    ANTENNAGATEAREA 0.196500 ;
    ANTENNADIFFAREA 0.434700 ;
    PORT
      LAYER met3 ;
        RECT 0.000 199.960 4.000 200.560 ;
    END
  END inputB[9]
  PIN opcode[0]
    DIRECTION INPUT ;
    USE SIGNAL ;
    ANTENNAGATEAREA 0.213000 ;
    ANTENNADIFFAREA 0.434700 ;
    PORT
      LAYER met3 ;
        RECT 0.000 293.800 4.000 294.400 ;
    END
  END opcode[0]
  PIN opcode[1]
    DIRECTION INPUT ;
    USE SIGNAL ;
    ANTENNAGATEAREA 0.213000 ;
    ANTENNADIFFAREA 0.434700 ;
    PORT
      LAYER met3 ;
        RECT 0.000 297.880 4.000 298.480 ;
    END
  END opcode[1]
  PIN outputC[0]
    DIRECTION OUTPUT ;
    USE SIGNAL ;
    ANTENNADIFFAREA 0.795200 ;
    PORT
      LAYER met3 ;
        RECT 509.145 2.760 513.145 3.360 ;
    END
  END outputC[0]
  PIN outputC[10]
    DIRECTION OUTPUT ;
    USE SIGNAL ;
    ANTENNADIFFAREA 0.445500 ;
    PORT
      LAYER met3 ;
        RECT 509.145 57.160 513.145 57.760 ;
    END
  END outputC[10]
  PIN outputC[11]
    DIRECTION OUTPUT ;
    USE SIGNAL ;
    ANTENNADIFFAREA 0.445500 ;
    PORT
      LAYER met3 ;
        RECT 509.145 62.600 513.145 63.200 ;
    END
  END outputC[11]
  PIN outputC[12]
    DIRECTION OUTPUT ;
    USE SIGNAL ;
    ANTENNADIFFAREA 0.445500 ;
    PORT
      LAYER met3 ;
        RECT 509.145 68.040 513.145 68.640 ;
    END
  END outputC[12]
  PIN outputC[13]
    DIRECTION OUTPUT ;
    USE SIGNAL ;
    ANTENNADIFFAREA 0.445500 ;
    PORT
      LAYER met3 ;
        RECT 509.145 73.480 513.145 74.080 ;
    END
  END outputC[13]
  PIN outputC[14]
    DIRECTION OUTPUT ;
    USE SIGNAL ;
    ANTENNADIFFAREA 0.445500 ;
    PORT
      LAYER met3 ;
        RECT 509.145 78.920 513.145 79.520 ;
    END
  END outputC[14]
  PIN outputC[15]
    DIRECTION OUTPUT ;
    USE SIGNAL ;
    ANTENNADIFFAREA 0.445500 ;
    PORT
      LAYER met3 ;
        RECT 509.145 84.360 513.145 84.960 ;
    END
  END outputC[15]
  PIN outputC[16]
    DIRECTION OUTPUT ;
    USE SIGNAL ;
    ANTENNADIFFAREA 0.445500 ;
    PORT
      LAYER met3 ;
        RECT 509.145 89.800 513.145 90.400 ;
    END
  END outputC[16]
  PIN outputC[17]
    DIRECTION OUTPUT ;
    USE SIGNAL ;
    ANTENNADIFFAREA 0.445500 ;
    PORT
      LAYER met3 ;
        RECT 509.145 95.240 513.145 95.840 ;
    END
  END outputC[17]
  PIN outputC[18]
    DIRECTION OUTPUT ;
    USE SIGNAL ;
    ANTENNADIFFAREA 0.445500 ;
    PORT
      LAYER met3 ;
        RECT 509.145 100.680 513.145 101.280 ;
    END
  END outputC[18]
  PIN outputC[19]
    DIRECTION OUTPUT ;
    USE SIGNAL ;
    ANTENNADIFFAREA 0.445500 ;
    PORT
      LAYER met3 ;
        RECT 509.145 106.120 513.145 106.720 ;
    END
  END outputC[19]
  PIN outputC[1]
    DIRECTION OUTPUT ;
    USE SIGNAL ;
    ANTENNADIFFAREA 0.445500 ;
    PORT
      LAYER met3 ;
        RECT 509.145 8.200 513.145 8.800 ;
    END
  END outputC[1]
  PIN outputC[20]
    DIRECTION OUTPUT ;
    USE SIGNAL ;
    ANTENNADIFFAREA 0.445500 ;
    PORT
      LAYER met3 ;
        RECT 509.145 111.560 513.145 112.160 ;
    END
  END outputC[20]
  PIN outputC[21]
    DIRECTION OUTPUT ;
    USE SIGNAL ;
    ANTENNADIFFAREA 0.445500 ;
    PORT
      LAYER met3 ;
        RECT 509.145 117.000 513.145 117.600 ;
    END
  END outputC[21]
  PIN outputC[22]
    DIRECTION OUTPUT ;
    USE SIGNAL ;
    ANTENNADIFFAREA 0.445500 ;
    PORT
      LAYER met3 ;
        RECT 509.145 122.440 513.145 123.040 ;
    END
  END outputC[22]
  PIN outputC[23]
    DIRECTION OUTPUT ;
    USE SIGNAL ;
    ANTENNADIFFAREA 0.445500 ;
    PORT
      LAYER met3 ;
        RECT 509.145 127.880 513.145 128.480 ;
    END
  END outputC[23]
  PIN outputC[24]
    DIRECTION OUTPUT ;
    USE SIGNAL ;
    ANTENNADIFFAREA 0.445500 ;
    PORT
      LAYER met3 ;
        RECT 509.145 133.320 513.145 133.920 ;
    END
  END outputC[24]
  PIN outputC[25]
    DIRECTION OUTPUT ;
    USE SIGNAL ;
    ANTENNADIFFAREA 0.445500 ;
    PORT
      LAYER met3 ;
        RECT 509.145 138.760 513.145 139.360 ;
    END
  END outputC[25]
  PIN outputC[26]
    DIRECTION OUTPUT ;
    USE SIGNAL ;
    ANTENNADIFFAREA 0.445500 ;
    PORT
      LAYER met3 ;
        RECT 509.145 144.200 513.145 144.800 ;
    END
  END outputC[26]
  PIN outputC[27]
    DIRECTION OUTPUT ;
    USE SIGNAL ;
    ANTENNADIFFAREA 0.445500 ;
    PORT
      LAYER met3 ;
        RECT 509.145 149.640 513.145 150.240 ;
    END
  END outputC[27]
  PIN outputC[28]
    DIRECTION OUTPUT ;
    USE SIGNAL ;
    ANTENNADIFFAREA 0.445500 ;
    PORT
      LAYER met3 ;
        RECT 509.145 155.080 513.145 155.680 ;
    END
  END outputC[28]
  PIN outputC[29]
    DIRECTION OUTPUT ;
    USE SIGNAL ;
    ANTENNADIFFAREA 0.445500 ;
    PORT
      LAYER met3 ;
        RECT 509.145 160.520 513.145 161.120 ;
    END
  END outputC[29]
  PIN outputC[2]
    DIRECTION OUTPUT ;
    USE SIGNAL ;
    ANTENNADIFFAREA 0.445500 ;
    PORT
      LAYER met3 ;
        RECT 509.145 13.640 513.145 14.240 ;
    END
  END outputC[2]
  PIN outputC[30]
    DIRECTION OUTPUT ;
    USE SIGNAL ;
    ANTENNADIFFAREA 0.445500 ;
    PORT
      LAYER met3 ;
        RECT 509.145 165.960 513.145 166.560 ;
    END
  END outputC[30]
  PIN outputC[31]
    DIRECTION OUTPUT ;
    USE SIGNAL ;
    ANTENNADIFFAREA 0.445500 ;
    PORT
      LAYER met3 ;
        RECT 509.145 171.400 513.145 172.000 ;
    END
  END outputC[31]
  PIN outputC[3]
    DIRECTION OUTPUT ;
    USE SIGNAL ;
    ANTENNADIFFAREA 0.445500 ;
    PORT
      LAYER met3 ;
        RECT 509.145 19.080 513.145 19.680 ;
    END
  END outputC[3]
  PIN outputC[4]
    DIRECTION OUTPUT ;
    USE SIGNAL ;
    ANTENNADIFFAREA 0.445500 ;
    PORT
      LAYER met3 ;
        RECT 509.145 24.520 513.145 25.120 ;
    END
  END outputC[4]
  PIN outputC[5]
    DIRECTION OUTPUT ;
    USE SIGNAL ;
    ANTENNADIFFAREA 0.445500 ;
    PORT
      LAYER met3 ;
        RECT 509.145 29.960 513.145 30.560 ;
    END
  END outputC[5]
  PIN outputC[6]
    DIRECTION OUTPUT ;
    USE SIGNAL ;
    ANTENNADIFFAREA 0.445500 ;
    PORT
      LAYER met3 ;
        RECT 509.145 35.400 513.145 36.000 ;
    END
  END outputC[6]
  PIN outputC[7]
    DIRECTION OUTPUT ;
    USE SIGNAL ;
    ANTENNADIFFAREA 0.445500 ;
    PORT
      LAYER met3 ;
        RECT 509.145 40.840 513.145 41.440 ;
    END
  END outputC[7]
  PIN outputC[8]
    DIRECTION OUTPUT ;
    USE SIGNAL ;
    ANTENNADIFFAREA 0.445500 ;
    PORT
      LAYER met3 ;
        RECT 509.145 46.280 513.145 46.880 ;
    END
  END outputC[8]
  PIN outputC[9]
    DIRECTION OUTPUT ;
    USE SIGNAL ;
    ANTENNADIFFAREA 0.445500 ;
    PORT
      LAYER met3 ;
        RECT 509.145 51.720 513.145 52.320 ;
    END
  END outputC[9]
  OBS
      LAYER nwell ;
        RECT 5.330 10.795 507.570 511.445 ;
      LAYER li1 ;
        RECT 5.520 10.795 507.380 511.445 ;
      LAYER met1 ;
        RECT 5.520 10.640 510.990 511.600 ;
      LAYER met2 ;
        RECT 5.610 2.875 510.960 520.045 ;
      LAYER met3 ;
        RECT 4.000 519.160 508.745 520.025 ;
        RECT 4.000 515.120 510.075 519.160 ;
        RECT 4.000 513.720 508.745 515.120 ;
        RECT 4.000 509.680 510.075 513.720 ;
        RECT 4.000 508.280 508.745 509.680 ;
        RECT 4.000 504.240 510.075 508.280 ;
        RECT 4.000 502.840 508.745 504.240 ;
        RECT 4.000 498.800 510.075 502.840 ;
        RECT 4.000 497.400 508.745 498.800 ;
        RECT 4.000 494.720 510.075 497.400 ;
        RECT 4.400 493.360 510.075 494.720 ;
        RECT 4.400 493.320 508.745 493.360 ;
        RECT 4.000 491.960 508.745 493.320 ;
        RECT 4.000 490.640 510.075 491.960 ;
        RECT 4.400 489.240 510.075 490.640 ;
        RECT 4.000 487.920 510.075 489.240 ;
        RECT 4.000 486.560 508.745 487.920 ;
        RECT 4.400 486.520 508.745 486.560 ;
        RECT 4.400 485.160 510.075 486.520 ;
        RECT 4.000 482.480 510.075 485.160 ;
        RECT 4.400 481.080 508.745 482.480 ;
        RECT 4.000 478.400 510.075 481.080 ;
        RECT 4.400 477.040 510.075 478.400 ;
        RECT 4.400 477.000 508.745 477.040 ;
        RECT 4.000 475.640 508.745 477.000 ;
        RECT 4.000 474.320 510.075 475.640 ;
        RECT 4.400 472.920 510.075 474.320 ;
        RECT 4.000 471.600 510.075 472.920 ;
        RECT 4.000 470.240 508.745 471.600 ;
        RECT 4.400 470.200 508.745 470.240 ;
        RECT 4.400 468.840 510.075 470.200 ;
        RECT 4.000 466.160 510.075 468.840 ;
        RECT 4.400 464.760 508.745 466.160 ;
        RECT 4.000 462.080 510.075 464.760 ;
        RECT 4.400 460.720 510.075 462.080 ;
        RECT 4.400 460.680 508.745 460.720 ;
        RECT 4.000 459.320 508.745 460.680 ;
        RECT 4.000 458.000 510.075 459.320 ;
        RECT 4.400 456.600 510.075 458.000 ;
        RECT 4.000 455.280 510.075 456.600 ;
        RECT 4.000 453.920 508.745 455.280 ;
        RECT 4.400 453.880 508.745 453.920 ;
        RECT 4.400 452.520 510.075 453.880 ;
        RECT 4.000 449.840 510.075 452.520 ;
        RECT 4.400 448.440 508.745 449.840 ;
        RECT 4.000 445.760 510.075 448.440 ;
        RECT 4.400 444.400 510.075 445.760 ;
        RECT 4.400 444.360 508.745 444.400 ;
        RECT 4.000 443.000 508.745 444.360 ;
        RECT 4.000 441.680 510.075 443.000 ;
        RECT 4.400 440.280 510.075 441.680 ;
        RECT 4.000 438.960 510.075 440.280 ;
        RECT 4.000 437.600 508.745 438.960 ;
        RECT 4.400 437.560 508.745 437.600 ;
        RECT 4.400 436.200 510.075 437.560 ;
        RECT 4.000 433.520 510.075 436.200 ;
        RECT 4.400 432.120 508.745 433.520 ;
        RECT 4.000 429.440 510.075 432.120 ;
        RECT 4.400 428.080 510.075 429.440 ;
        RECT 4.400 428.040 508.745 428.080 ;
        RECT 4.000 426.680 508.745 428.040 ;
        RECT 4.000 425.360 510.075 426.680 ;
        RECT 4.400 423.960 510.075 425.360 ;
        RECT 4.000 422.640 510.075 423.960 ;
        RECT 4.000 421.280 508.745 422.640 ;
        RECT 4.400 421.240 508.745 421.280 ;
        RECT 4.400 419.880 510.075 421.240 ;
        RECT 4.000 417.200 510.075 419.880 ;
        RECT 4.400 415.800 508.745 417.200 ;
        RECT 4.000 413.120 510.075 415.800 ;
        RECT 4.400 411.760 510.075 413.120 ;
        RECT 4.400 411.720 508.745 411.760 ;
        RECT 4.000 410.360 508.745 411.720 ;
        RECT 4.000 409.040 510.075 410.360 ;
        RECT 4.400 407.640 510.075 409.040 ;
        RECT 4.000 406.320 510.075 407.640 ;
        RECT 4.000 404.960 508.745 406.320 ;
        RECT 4.400 404.920 508.745 404.960 ;
        RECT 4.400 403.560 510.075 404.920 ;
        RECT 4.000 400.880 510.075 403.560 ;
        RECT 4.400 399.480 508.745 400.880 ;
        RECT 4.000 396.800 510.075 399.480 ;
        RECT 4.400 395.440 510.075 396.800 ;
        RECT 4.400 395.400 508.745 395.440 ;
        RECT 4.000 394.040 508.745 395.400 ;
        RECT 4.000 392.720 510.075 394.040 ;
        RECT 4.400 391.320 510.075 392.720 ;
        RECT 4.000 390.000 510.075 391.320 ;
        RECT 4.000 388.640 508.745 390.000 ;
        RECT 4.400 388.600 508.745 388.640 ;
        RECT 4.400 387.240 510.075 388.600 ;
        RECT 4.000 384.560 510.075 387.240 ;
        RECT 4.400 383.160 508.745 384.560 ;
        RECT 4.000 380.480 510.075 383.160 ;
        RECT 4.400 379.120 510.075 380.480 ;
        RECT 4.400 379.080 508.745 379.120 ;
        RECT 4.000 377.720 508.745 379.080 ;
        RECT 4.000 376.400 510.075 377.720 ;
        RECT 4.400 375.000 510.075 376.400 ;
        RECT 4.000 373.680 510.075 375.000 ;
        RECT 4.000 372.320 508.745 373.680 ;
        RECT 4.400 372.280 508.745 372.320 ;
        RECT 4.400 370.920 510.075 372.280 ;
        RECT 4.000 368.240 510.075 370.920 ;
        RECT 4.400 366.840 508.745 368.240 ;
        RECT 4.000 364.160 510.075 366.840 ;
        RECT 4.400 362.800 510.075 364.160 ;
        RECT 4.400 362.760 508.745 362.800 ;
        RECT 4.000 361.400 508.745 362.760 ;
        RECT 4.000 360.080 510.075 361.400 ;
        RECT 4.400 358.680 510.075 360.080 ;
        RECT 4.000 357.360 510.075 358.680 ;
        RECT 4.000 356.000 508.745 357.360 ;
        RECT 4.400 355.960 508.745 356.000 ;
        RECT 4.400 354.600 510.075 355.960 ;
        RECT 4.000 351.920 510.075 354.600 ;
        RECT 4.400 350.520 508.745 351.920 ;
        RECT 4.000 347.840 510.075 350.520 ;
        RECT 4.400 346.480 510.075 347.840 ;
        RECT 4.400 346.440 508.745 346.480 ;
        RECT 4.000 345.080 508.745 346.440 ;
        RECT 4.000 343.760 510.075 345.080 ;
        RECT 4.400 342.360 510.075 343.760 ;
        RECT 4.000 341.040 510.075 342.360 ;
        RECT 4.000 339.680 508.745 341.040 ;
        RECT 4.400 339.640 508.745 339.680 ;
        RECT 4.400 338.280 510.075 339.640 ;
        RECT 4.000 335.600 510.075 338.280 ;
        RECT 4.400 334.200 508.745 335.600 ;
        RECT 4.000 331.520 510.075 334.200 ;
        RECT 4.400 330.160 510.075 331.520 ;
        RECT 4.400 330.120 508.745 330.160 ;
        RECT 4.000 328.760 508.745 330.120 ;
        RECT 4.000 327.440 510.075 328.760 ;
        RECT 4.400 326.040 510.075 327.440 ;
        RECT 4.000 324.720 510.075 326.040 ;
        RECT 4.000 323.360 508.745 324.720 ;
        RECT 4.400 323.320 508.745 323.360 ;
        RECT 4.400 321.960 510.075 323.320 ;
        RECT 4.000 319.280 510.075 321.960 ;
        RECT 4.400 317.880 508.745 319.280 ;
        RECT 4.000 315.200 510.075 317.880 ;
        RECT 4.400 313.840 510.075 315.200 ;
        RECT 4.400 313.800 508.745 313.840 ;
        RECT 4.000 312.440 508.745 313.800 ;
        RECT 4.000 311.120 510.075 312.440 ;
        RECT 4.400 309.720 510.075 311.120 ;
        RECT 4.000 308.400 510.075 309.720 ;
        RECT 4.000 307.040 508.745 308.400 ;
        RECT 4.400 307.000 508.745 307.040 ;
        RECT 4.400 305.640 510.075 307.000 ;
        RECT 4.000 302.960 510.075 305.640 ;
        RECT 4.400 301.560 508.745 302.960 ;
        RECT 4.000 298.880 510.075 301.560 ;
        RECT 4.400 297.520 510.075 298.880 ;
        RECT 4.400 297.480 508.745 297.520 ;
        RECT 4.000 296.120 508.745 297.480 ;
        RECT 4.000 294.800 510.075 296.120 ;
        RECT 4.400 293.400 510.075 294.800 ;
        RECT 4.000 292.080 510.075 293.400 ;
        RECT 4.000 290.720 508.745 292.080 ;
        RECT 4.400 290.680 508.745 290.720 ;
        RECT 4.400 289.320 510.075 290.680 ;
        RECT 4.000 286.640 510.075 289.320 ;
        RECT 4.400 285.240 508.745 286.640 ;
        RECT 4.000 282.560 510.075 285.240 ;
        RECT 4.400 281.200 510.075 282.560 ;
        RECT 4.400 281.160 508.745 281.200 ;
        RECT 4.000 279.800 508.745 281.160 ;
        RECT 4.000 278.480 510.075 279.800 ;
        RECT 4.400 277.080 510.075 278.480 ;
        RECT 4.000 275.760 510.075 277.080 ;
        RECT 4.000 274.400 508.745 275.760 ;
        RECT 4.400 274.360 508.745 274.400 ;
        RECT 4.400 273.000 510.075 274.360 ;
        RECT 4.000 270.320 510.075 273.000 ;
        RECT 4.400 268.920 508.745 270.320 ;
        RECT 4.000 266.240 510.075 268.920 ;
        RECT 4.400 264.880 510.075 266.240 ;
        RECT 4.400 264.840 508.745 264.880 ;
        RECT 4.000 263.480 508.745 264.840 ;
        RECT 4.000 262.160 510.075 263.480 ;
        RECT 4.400 260.760 510.075 262.160 ;
        RECT 4.000 259.440 510.075 260.760 ;
        RECT 4.000 258.080 508.745 259.440 ;
        RECT 4.400 258.040 508.745 258.080 ;
        RECT 4.400 256.680 510.075 258.040 ;
        RECT 4.000 254.000 510.075 256.680 ;
        RECT 4.400 252.600 508.745 254.000 ;
        RECT 4.000 249.920 510.075 252.600 ;
        RECT 4.400 248.560 510.075 249.920 ;
        RECT 4.400 248.520 508.745 248.560 ;
        RECT 4.000 247.160 508.745 248.520 ;
        RECT 4.000 245.840 510.075 247.160 ;
        RECT 4.400 244.440 510.075 245.840 ;
        RECT 4.000 243.120 510.075 244.440 ;
        RECT 4.000 241.760 508.745 243.120 ;
        RECT 4.400 241.720 508.745 241.760 ;
        RECT 4.400 240.360 510.075 241.720 ;
        RECT 4.000 237.680 510.075 240.360 ;
        RECT 4.400 236.280 508.745 237.680 ;
        RECT 4.000 233.600 510.075 236.280 ;
        RECT 4.400 232.240 510.075 233.600 ;
        RECT 4.400 232.200 508.745 232.240 ;
        RECT 4.000 230.840 508.745 232.200 ;
        RECT 4.000 229.520 510.075 230.840 ;
        RECT 4.400 228.120 510.075 229.520 ;
        RECT 4.000 226.800 510.075 228.120 ;
        RECT 4.000 225.440 508.745 226.800 ;
        RECT 4.400 225.400 508.745 225.440 ;
        RECT 4.400 224.040 510.075 225.400 ;
        RECT 4.000 221.360 510.075 224.040 ;
        RECT 4.400 219.960 508.745 221.360 ;
        RECT 4.000 217.280 510.075 219.960 ;
        RECT 4.400 215.920 510.075 217.280 ;
        RECT 4.400 215.880 508.745 215.920 ;
        RECT 4.000 214.520 508.745 215.880 ;
        RECT 4.000 213.200 510.075 214.520 ;
        RECT 4.400 211.800 510.075 213.200 ;
        RECT 4.000 210.480 510.075 211.800 ;
        RECT 4.000 209.120 508.745 210.480 ;
        RECT 4.400 209.080 508.745 209.120 ;
        RECT 4.400 207.720 510.075 209.080 ;
        RECT 4.000 205.040 510.075 207.720 ;
        RECT 4.400 203.640 508.745 205.040 ;
        RECT 4.000 200.960 510.075 203.640 ;
        RECT 4.400 199.600 510.075 200.960 ;
        RECT 4.400 199.560 508.745 199.600 ;
        RECT 4.000 198.200 508.745 199.560 ;
        RECT 4.000 196.880 510.075 198.200 ;
        RECT 4.400 195.480 510.075 196.880 ;
        RECT 4.000 194.160 510.075 195.480 ;
        RECT 4.000 192.800 508.745 194.160 ;
        RECT 4.400 192.760 508.745 192.800 ;
        RECT 4.400 191.400 510.075 192.760 ;
        RECT 4.000 188.720 510.075 191.400 ;
        RECT 4.400 187.320 508.745 188.720 ;
        RECT 4.000 184.640 510.075 187.320 ;
        RECT 4.400 183.280 510.075 184.640 ;
        RECT 4.400 183.240 508.745 183.280 ;
        RECT 4.000 181.880 508.745 183.240 ;
        RECT 4.000 180.560 510.075 181.880 ;
        RECT 4.400 179.160 510.075 180.560 ;
        RECT 4.000 177.840 510.075 179.160 ;
        RECT 4.000 176.480 508.745 177.840 ;
        RECT 4.400 176.440 508.745 176.480 ;
        RECT 4.400 175.080 510.075 176.440 ;
        RECT 4.000 172.400 510.075 175.080 ;
        RECT 4.400 171.000 508.745 172.400 ;
        RECT 4.000 168.320 510.075 171.000 ;
        RECT 4.400 166.960 510.075 168.320 ;
        RECT 4.400 166.920 508.745 166.960 ;
        RECT 4.000 165.560 508.745 166.920 ;
        RECT 4.000 164.240 510.075 165.560 ;
        RECT 4.400 162.840 510.075 164.240 ;
        RECT 4.000 161.520 510.075 162.840 ;
        RECT 4.000 160.160 508.745 161.520 ;
        RECT 4.400 160.120 508.745 160.160 ;
        RECT 4.400 158.760 510.075 160.120 ;
        RECT 4.000 156.080 510.075 158.760 ;
        RECT 4.400 154.680 508.745 156.080 ;
        RECT 4.000 152.000 510.075 154.680 ;
        RECT 4.400 150.640 510.075 152.000 ;
        RECT 4.400 150.600 508.745 150.640 ;
        RECT 4.000 149.240 508.745 150.600 ;
        RECT 4.000 147.920 510.075 149.240 ;
        RECT 4.400 146.520 510.075 147.920 ;
        RECT 4.000 145.200 510.075 146.520 ;
        RECT 4.000 143.840 508.745 145.200 ;
        RECT 4.400 143.800 508.745 143.840 ;
        RECT 4.400 142.440 510.075 143.800 ;
        RECT 4.000 139.760 510.075 142.440 ;
        RECT 4.400 138.360 508.745 139.760 ;
        RECT 4.000 135.680 510.075 138.360 ;
        RECT 4.400 134.320 510.075 135.680 ;
        RECT 4.400 134.280 508.745 134.320 ;
        RECT 4.000 132.920 508.745 134.280 ;
        RECT 4.000 131.600 510.075 132.920 ;
        RECT 4.400 130.200 510.075 131.600 ;
        RECT 4.000 128.880 510.075 130.200 ;
        RECT 4.000 127.520 508.745 128.880 ;
        RECT 4.400 127.480 508.745 127.520 ;
        RECT 4.400 126.120 510.075 127.480 ;
        RECT 4.000 123.440 510.075 126.120 ;
        RECT 4.400 122.040 508.745 123.440 ;
        RECT 4.000 119.360 510.075 122.040 ;
        RECT 4.400 118.000 510.075 119.360 ;
        RECT 4.400 117.960 508.745 118.000 ;
        RECT 4.000 116.600 508.745 117.960 ;
        RECT 4.000 115.280 510.075 116.600 ;
        RECT 4.400 113.880 510.075 115.280 ;
        RECT 4.000 112.560 510.075 113.880 ;
        RECT 4.000 111.200 508.745 112.560 ;
        RECT 4.400 111.160 508.745 111.200 ;
        RECT 4.400 109.800 510.075 111.160 ;
        RECT 4.000 107.120 510.075 109.800 ;
        RECT 4.400 105.720 508.745 107.120 ;
        RECT 4.000 103.040 510.075 105.720 ;
        RECT 4.400 101.680 510.075 103.040 ;
        RECT 4.400 101.640 508.745 101.680 ;
        RECT 4.000 100.280 508.745 101.640 ;
        RECT 4.000 98.960 510.075 100.280 ;
        RECT 4.400 97.560 510.075 98.960 ;
        RECT 4.000 96.240 510.075 97.560 ;
        RECT 4.000 94.880 508.745 96.240 ;
        RECT 4.400 94.840 508.745 94.880 ;
        RECT 4.400 93.480 510.075 94.840 ;
        RECT 4.000 90.800 510.075 93.480 ;
        RECT 4.400 89.400 508.745 90.800 ;
        RECT 4.000 86.720 510.075 89.400 ;
        RECT 4.400 85.360 510.075 86.720 ;
        RECT 4.400 85.320 508.745 85.360 ;
        RECT 4.000 83.960 508.745 85.320 ;
        RECT 4.000 82.640 510.075 83.960 ;
        RECT 4.400 81.240 510.075 82.640 ;
        RECT 4.000 79.920 510.075 81.240 ;
        RECT 4.000 78.560 508.745 79.920 ;
        RECT 4.400 78.520 508.745 78.560 ;
        RECT 4.400 77.160 510.075 78.520 ;
        RECT 4.000 74.480 510.075 77.160 ;
        RECT 4.400 73.080 508.745 74.480 ;
        RECT 4.000 70.400 510.075 73.080 ;
        RECT 4.400 69.040 510.075 70.400 ;
        RECT 4.400 69.000 508.745 69.040 ;
        RECT 4.000 67.640 508.745 69.000 ;
        RECT 4.000 66.320 510.075 67.640 ;
        RECT 4.400 64.920 510.075 66.320 ;
        RECT 4.000 63.600 510.075 64.920 ;
        RECT 4.000 62.240 508.745 63.600 ;
        RECT 4.400 62.200 508.745 62.240 ;
        RECT 4.400 60.840 510.075 62.200 ;
        RECT 4.000 58.160 510.075 60.840 ;
        RECT 4.400 56.760 508.745 58.160 ;
        RECT 4.000 54.080 510.075 56.760 ;
        RECT 4.400 52.720 510.075 54.080 ;
        RECT 4.400 52.680 508.745 52.720 ;
        RECT 4.000 51.320 508.745 52.680 ;
        RECT 4.000 50.000 510.075 51.320 ;
        RECT 4.400 48.600 510.075 50.000 ;
        RECT 4.000 47.280 510.075 48.600 ;
        RECT 4.000 45.920 508.745 47.280 ;
        RECT 4.400 45.880 508.745 45.920 ;
        RECT 4.400 44.520 510.075 45.880 ;
        RECT 4.000 41.840 510.075 44.520 ;
        RECT 4.400 40.440 508.745 41.840 ;
        RECT 4.000 37.760 510.075 40.440 ;
        RECT 4.400 36.400 510.075 37.760 ;
        RECT 4.400 36.360 508.745 36.400 ;
        RECT 4.000 35.000 508.745 36.360 ;
        RECT 4.000 33.680 510.075 35.000 ;
        RECT 4.400 32.280 510.075 33.680 ;
        RECT 4.000 30.960 510.075 32.280 ;
        RECT 4.000 29.600 508.745 30.960 ;
        RECT 4.400 29.560 508.745 29.600 ;
        RECT 4.400 28.200 510.075 29.560 ;
        RECT 4.000 25.520 510.075 28.200 ;
        RECT 4.000 24.120 508.745 25.520 ;
        RECT 4.000 20.080 510.075 24.120 ;
        RECT 4.000 18.680 508.745 20.080 ;
        RECT 4.000 14.640 510.075 18.680 ;
        RECT 4.000 13.240 508.745 14.640 ;
        RECT 4.000 9.200 510.075 13.240 ;
        RECT 4.000 7.800 508.745 9.200 ;
        RECT 4.000 3.760 510.075 7.800 ;
        RECT 4.000 2.895 508.745 3.760 ;
      LAYER met4 ;
        RECT 9.495 28.735 24.320 510.505 ;
        RECT 26.720 28.735 27.620 510.505 ;
        RECT 30.020 28.735 74.320 510.505 ;
        RECT 76.720 28.735 77.620 510.505 ;
        RECT 80.020 28.735 124.320 510.505 ;
        RECT 126.720 28.735 127.620 510.505 ;
        RECT 130.020 28.735 174.320 510.505 ;
        RECT 176.720 28.735 177.620 510.505 ;
        RECT 180.020 28.735 224.320 510.505 ;
        RECT 226.720 28.735 227.620 510.505 ;
        RECT 230.020 28.735 274.320 510.505 ;
        RECT 276.720 28.735 277.620 510.505 ;
        RECT 280.020 28.735 324.320 510.505 ;
        RECT 326.720 28.735 327.620 510.505 ;
        RECT 330.020 28.735 374.320 510.505 ;
        RECT 376.720 28.735 377.620 510.505 ;
        RECT 380.020 28.735 424.320 510.505 ;
        RECT 426.720 28.735 427.620 510.505 ;
        RECT 430.020 28.735 474.320 510.505 ;
        RECT 476.720 28.735 477.620 510.505 ;
        RECT 480.020 28.735 501.105 510.505 ;
      LAYER met5 ;
        RECT 412.740 323.900 484.260 325.500 ;
  END
END TopModule
END LIBRARY

